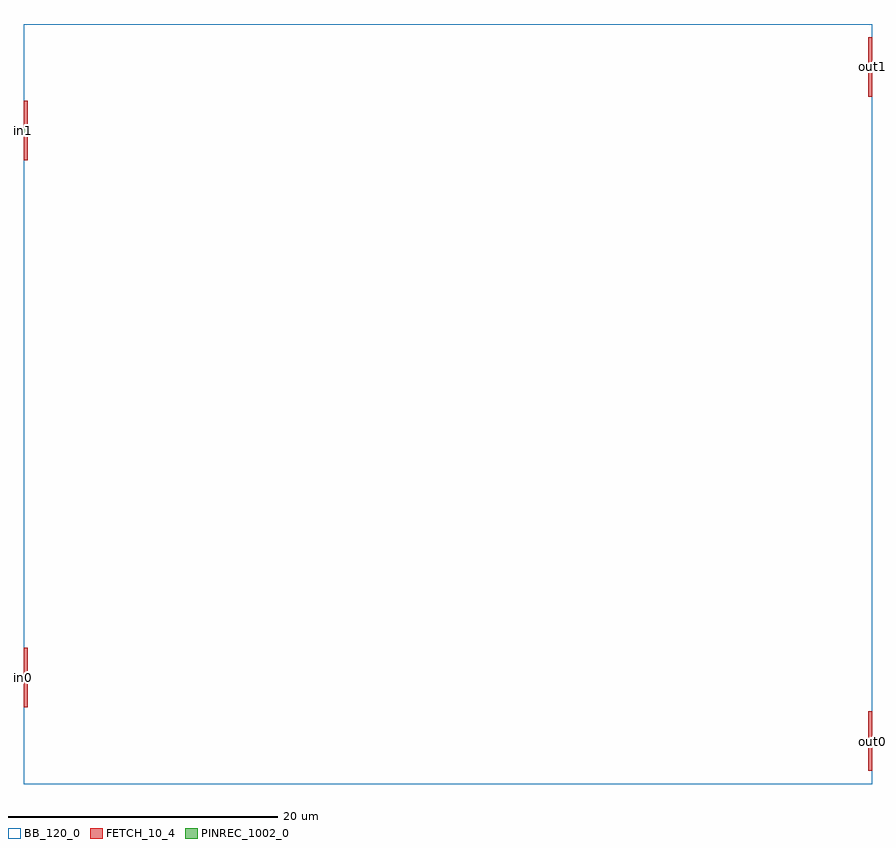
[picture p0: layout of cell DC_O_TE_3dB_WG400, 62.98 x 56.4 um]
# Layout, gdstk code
import gdstk
lib = gdstk.Library(unit=1e-6, precision=1e-09)
def R(c, l, rs):  # rectangles x0, y0, x1, y1
    for r in rs: c.add(gdstk.rectangle(r[:2], r[2:], *l))
FETCH_10_4 = (10, 4)
BB_120_0 = (120, 0)
PINREC_1002_0 = (1002, 0)

dc_o_te_3db_wg400 = lib.new_cell('DC_O_TE_3dB_WG400')
R(dc_o_te_3db_wg400, FETCH_10_4, [(62.682,1,62.982,3), (62.682,3.4,62.982,5.4), (0,5.7,0.3,7.7), (0,8.1,0.3,10.1), (0,46.3,0.3,48.3), (0,48.7,0.3,50.7), (62.682,51,62.982,53), (62.682,53.4,62.982,55.4)])
R(dc_o_te_3db_wg400, BB_120_0, [(0,0,62.982,56.401)])
R(dc_o_te_3db_wg400, PINREC_1002_0, [(62.682,3,62.982,3.4), (0,7.7,0.3,8.1), (0,48.3,0.3,48.7), (62.682,53,62.982,53.4)])
dc_o_te_3db_wg400.add(gdstk.Label('out1', (62.982,53.21), layer=1000, texttype=0))
dc_o_te_3db_wg400.add(gdstk.Label('out0', (62.982,3.187), layer=1000, texttype=0))
dc_o_te_3db_wg400.add(gdstk.Label('in1', (0,48.508), layer=1000, texttype=0))
dc_o_te_3db_wg400.add(gdstk.Label('in0', (0,7.903), layer=1000, texttype=0))

lib.write_gds('DC_O_TE_3dB_WG400.gds')
